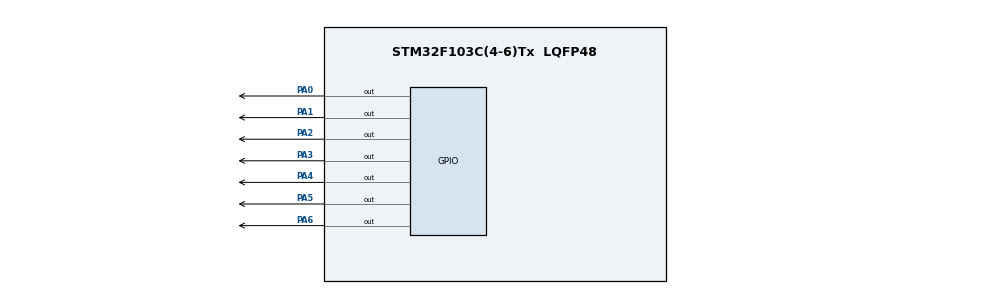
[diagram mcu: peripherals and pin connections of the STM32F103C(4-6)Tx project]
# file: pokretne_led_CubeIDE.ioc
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Mcu.Family=STM32F1
Mcu.Name=STM32F103C(4-6)Tx
Mcu.Package=LQFP48
NVIC.PriorityGroup=NVIC_PRIORITYGROUP_4
PA0-WKUP.Signal=GPIO_Output
PA1.Signal=GPIO_Output
PA2.Signal=GPIO_Output
PA3.Signal=GPIO_Output
PA4.Signal=GPIO_Output
PA5.Signal=GPIO_Output
PA6.Signal=GPIO_Output
ProjectManager.HeapSize=0x200
ProjectManager.StackSize=0x400
ProjectManager.TargetToolchain=STM32CubeIDE
RCC.AHBFreq_Value=28000000
RCC.APB1Freq_Value=28000000
RCC.APB1TimFreq_Value=28000000
RCC.APB2Freq_Value=28000000
RCC.APB2TimFreq_Value=28000000
RCC.HCLKFreq_Value=28000000
RCC.PLLMUL=RCC_PLL_MUL7
RCC.SYSCLKFreq_VALUE=28000000
RCC.SYSCLKSource=RCC_SYSCLKSOURCE_PLLCLK
RCC.USBFreq_Value=28000000
VP_SYS_VS_ND.Mode=No_Debug
board=custom

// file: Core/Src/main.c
/* USER CODE BEGIN Header */
/**
  ******************************************************************************
  * @file           : main.c
  * @brief          : Main program body
  ******************************************************************************
  * @attention
  *
  * <h2><center>&copy; Copyright (c) 2021 STMicroelectronics.
  * All rights reserved.</center></h2>
  *
  * This software component is licensed by ST under BSD 3-Clause license,
  * the "License"; You may not use this file except in compliance with the
  * License. You may obtain a copy of the License at:
  *                        opensource.org/licenses/BSD-3-Clause
  *
  ******************************************************************************
  */
/* USER CODE END Header */

#include "main.h"
#define led0 GPIO_PIN_0
#define led1 GPIO_PIN_1
#define led2 GPIO_PIN_2
#define led3 GPIO_PIN_3
#define led4 GPIO_PIN_4
#define led5 GPIO_PIN_5
#define led6 GPIO_PIN_6
#define led7 GPIO_PIN_7
int LEDS[] = {led0, led1, led2, led3, led4, led5, led6, led7};

void SystemClock_Config(void);

int main(void)
{
	int j;

  /* MCU Configuration--------------------------------------------------------*/

  /* Reset of all peripherals, Initializes the Flash interface and the Systick. */
  HAL_Init();

  /* Configure the system clock */
  SystemClock_Config();

  /* Initialize all configured peripherals */

  /* Infinite loop */
  while (1)
  {
	  for(j = 0; j <= 7; j++)
	  	  {
	  		  HAL_GPIO_WritePin(GPIOA,LEDS[j],GPIO_PIN_SET);
	  		  HAL_Delay(250);
	  		  HAL_GPIO_WritePin(GPIOA,LEDS[j],GPIO_PIN_RESET);
	  		  HAL_Delay(250);
	  	  }
  }
}

void SystemClock_Config(void)
{
  RCC_OscInitTypeDef RCC_OscInitStruct = {0};
  RCC_ClkInitTypeDef RCC_ClkInitStruct = {0};

  /** Initializes the CPU, AHB and APB busses clocks
  */
  RCC_OscInitStruct.OscillatorType = RCC_OSCILLATORTYPE_HSI;
  RCC_OscInitStruct.HSIState = RCC_HSI_ON;
  RCC_OscInitStruct.HSICalibrationValue = RCC_HSICALIBRATION_DEFAULT;
  RCC_OscInitStruct.PLL.PLLState = RCC_PLL_NONE;
  if (HAL_RCC_OscConfig(&RCC_OscInitStruct) != HAL_OK)
  {
    Error_Handler();
  }
  /** Initializes the CPU, AHB and APB busses clocks
  */
  RCC_ClkInitStruct.ClockType = RCC_CLOCKTYPE_HCLK|RCC_CLOCKTYPE_SYSCLK
                              |RCC_CLOCKTYPE_PCLK1|RCC_CLOCKTYPE_PCLK2;
  RCC_ClkInitStruct.SYSCLKSource = RCC_SYSCLKSOURCE_HSI;
  RCC_ClkInitStruct.AHBCLKDivider = RCC_SYSCLK_DIV1;
  RCC_ClkInitStruct.APB1CLKDivider = RCC_HCLK_DIV1;
  RCC_ClkInitStruct.APB2CLKDivider = RCC_HCLK_DIV1;

  if (HAL_RCC_ClockConfig(&RCC_ClkInitStruct, FLASH_LATENCY_0) != HAL_OK)
  {
    Error_Handler();
  }
}

void Error_Handler(void)
{
}

/************************ (C) COPYRIGHT STMicroelectronics *****END OF FILE****/
